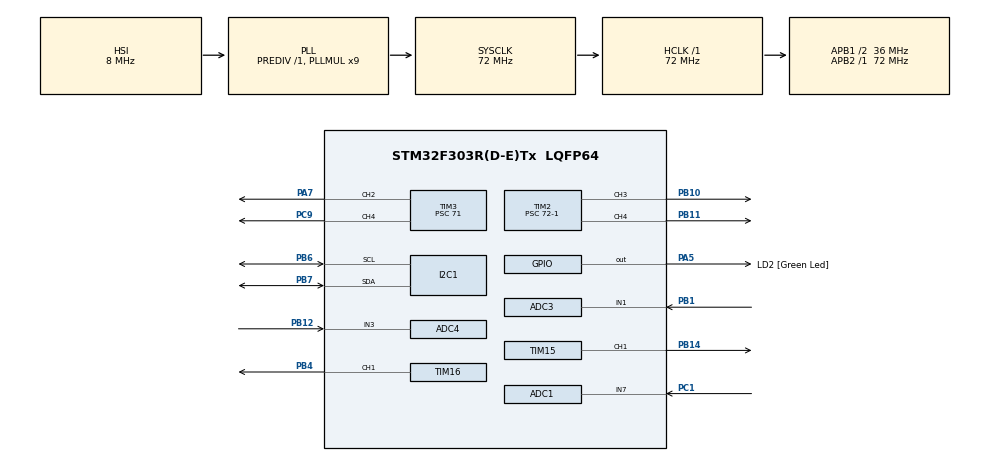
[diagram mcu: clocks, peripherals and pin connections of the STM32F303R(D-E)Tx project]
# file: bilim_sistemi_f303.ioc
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ADC1.Channel-0\#ChannelRegularConversion=ADC_CHANNEL_7
ADC1.NbrOfConversionFlag=1
ADC1.Offset-0\#ChannelRegularConversion=0
ADC1.OffsetNumber-0\#ChannelRegularConversion=ADC_OFFSET_NONE
ADC1.Rank-0\#ChannelRegularConversion=1
ADC1.SamplingTime-0\#ChannelRegularConversion=ADC_SAMPLETIME_19CYCLES_5
ADC1.master=1
ADC3.Channel-0\#ChannelRegularConversion=ADC_CHANNEL_1
ADC3.NbrOfConversionFlag=1
ADC3.Offset-0\#ChannelRegularConversion=0
ADC3.OffsetNumber-0\#ChannelRegularConversion=ADC_OFFSET_NONE
ADC3.Rank-0\#ChannelRegularConversion=1
ADC3.SamplingTime-0\#ChannelRegularConversion=ADC_SAMPLETIME_1CYCLE_5
ADC3.SamplingTimeOPAMP-0\#ChannelRegularConversion=ADC_SAMPLETIME_61CYCLES_5
ADC3.master=1
ADC4.Channel-0\#ChannelRegularConversion=ADC_CHANNEL_3
ADC4.NbrOfConversionFlag=1
ADC4.Offset-0\#ChannelRegularConversion=0
ADC4.OffsetNumber-0\#ChannelRegularConversion=ADC_OFFSET_NONE
ADC4.Rank-0\#ChannelRegularConversion=1
ADC4.SamplingTime-0\#ChannelRegularConversion=ADC_SAMPLETIME_1CYCLE_5
ADC4.SamplingTimeOPAMP-0\#ChannelRegularConversion=ADC_SAMPLETIME_61CYCLES_5
Mcu.Family=STM32F3
Mcu.Name=STM32F303R(D-E)Tx
Mcu.Package=LQFP64
NVIC.PriorityGroup=NVIC_PRIORITYGROUP_0
PA12.Signal=S_TIM4_CH2
PA13.GPIO_Label=TMS
PA13.Mode=Serial_Wire
PA13.Signal=SYS_JTMS-SWDIO
PA14.GPIO_Label=TCK
PA14.Mode=Serial_Wire
PA14.Signal=SYS_JTCK-SWCLK
PA5.GPIO_Label=LD2 [Green Led]
PA5.GPIO_Mode=GPIO_MODE_OUTPUT_PP
PA5.GPIO_PuPd=GPIO_NOPULL
PA5.GPIO_Speed=GPIO_SPEED_FREQ_LOW
PA5.Signal=GPIO_Output
PA7.Signal=S_TIM3_CH2
PB1.Mode=IN1-Single-Ended
PB1.Signal=ADC3_IN1
PB10.Signal=S_TIM2_CH3
PB11.Signal=S_TIM2_CH4
PB12.Mode=IN3-Single-Ended
PB12.Signal=ADC4_IN3
PB14.Signal=S_TIM15_CH1
PB3.GPIO_Label=SWO
PB3.Signal=SYS_JTDO-TRACESWO
PB4.Signal=S_TIM16_CH1
PB6.Mode=I2C
PB6.Signal=I2C1_SCL
PB7.Mode=I2C
PB7.Signal=I2C1_SDA
PC1.Signal=ADCx_IN7
PC9.Signal=S_TIM3_CH4
PF0-OSC_IN.Mode=HSE-External-Clock-Source
PF0-OSC_IN.Signal=RCC_OSC_IN
ProjectManager.HeapSize=0x200
ProjectManager.StackSize=0x400
ProjectManager.TargetToolchain=STM32CubeIDE
RCC.AHBFreq_Value=72000000
RCC.APB1CLKDivider=RCC_HCLK_DIV2
RCC.APB1Freq_Value=36000000
RCC.APB1TimFreq_Value=72000000
RCC.APB2Freq_Value=72000000
RCC.APB2TimFreq_Value=72000000
RCC.CortexFreq_Value=72000000
RCC.HCLKFreq_Value=72000000
RCC.HSE_VALUE=8000000
RCC.HSI_VALUE=8000000
RCC.LSE_VALUE=32768
RCC.PLLM=8
RCC.PLLMUL=RCC_PLL_MUL9
RCC.PLLN=336
RCC.PLLP=RCC_PLLP_DIV4
RCC.PLLQ=7
RCC.PRESCALERUSB=RCC_USBCLKSOURCE_PLL_DIV1_5
RCC.RCC_PLLsource_Clock_Source_FROM_HSE=RCC_HSE_PREDIV_DIV2
RCC.SYSCLKFreq_VALUE=72000000
RCC.SYSCLKSourceVirtual=RCC_SYSCLKSOURCE_PLLCLK
RCC.USBFreq_Value=48000000
SH.ADCx_IN7.0=ADC1_IN7,IN7-Single-Ended
SH.S_TIM15_CH1.0=TIM15_CH1,PWM Generation1 CH1
SH.S_TIM16_CH1.0=TIM16_CH1,PWM Generation1 CH1
SH.S_TIM2_CH3.0=TIM2_CH3,PWM Generation3 CH3
SH.S_TIM2_CH4.0=TIM2_CH4,PWM Generation4 CH4
SH.S_TIM3_CH2.0=TIM3_CH2,PWM Generation2 CH2
SH.S_TIM3_CH4.0=TIM3_CH4,PWM Generation4 CH4
SH.S_TIM4_CH2.0=TIM4_CH2
TIM15.Channel-PWM\ Generation1\ CH1=TIM_CHANNEL_1
TIM15.Period=100
TIM15.Prescaler=71
TIM16.Channel=TIM_CHANNEL_1
TIM16.Period=100-1
TIM16.Prescaler=72-1
TIM16.Pulse=0
TIM2.Channel-PWM\ Generation3\ CH3=TIM_CHANNEL_3
TIM2.Channel-PWM\ Generation4\ CH4=TIM_CHANNEL_4
TIM2.Period=100-1
TIM2.Prescaler=72-1
TIM3.Channel-PWM\ Generation2\ CH2=TIM_CHANNEL_2
TIM3.Channel-PWM\ Generation4\ CH4=TIM_CHANNEL_4
TIM3.Period=99
TIM3.Prescaler=71
TIM8.Prescaler=71
VP_TIM16_VS_ClockSourceINT.Mode=Enable_Timer
VP_TIM1_VS_ClockSourceINT.Mode=Internal
VP_TIM2_VS_ClockSourceINT.Mode=Internal
VP_TIM8_VS_ClockSourceINT.Mode=Internal
board=NUCLEO-F303RE

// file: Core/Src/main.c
/* USER CODE BEGIN Header */
/**
  ******************************************************************************
  * @file           : main.c
  * @brief          : Main program body
  ******************************************************************************
  * @attention
  *
  * Copyright (c) 2024 STMicroelectronics.
  * All rights reserved.
  *
  * This software is licensed under terms that can be found in the LICENSE file
  * in the root directory of this software component.
  * If no LICENSE file comes with this software, it is provided AS-IS.
  *
  ******************************************************************************
  */
/* USER CODE END Header */
#include "main.h"

/* USER CODE BEGIN Includes */
#include "BMP180.h"
#include "MQ.h"
#include "mk_dht11.h"

/* USER CODE END Includes */

/* USER CODE BEGIN PD */
MQ mq137;
MQ mq4;
MQ mq135;
dht11_t DHT11;

/* USER CODE END PD */

ADC_HandleTypeDef hadc1;
ADC_HandleTypeDef hadc3;
ADC_HandleTypeDef hadc4;

I2C_HandleTypeDef hi2c1;

TIM_HandleTypeDef htim1;
TIM_HandleTypeDef htim2;
TIM_HandleTypeDef htim3;
TIM_HandleTypeDef htim8;
TIM_HandleTypeDef htim15;
TIM_HandleTypeDef htim16;

/* USER CODE BEGIN PV */
float TEMP;
float PRESS;
float temp = 0;
float hum = 0;
float nh3_ppm = 0;
float ch4_ppm = 0;
float co2_ppm = 0;
uint8_t dht_temp = 0;
uint8_t dht_hum = 0;
uint8_t Lim_s1=0;
uint8_t Lim_s2=0;

/* USER CODE END PV */

void SystemClock_Config(void);
static void MX_GPIO_Init(void);
static void MX_I2C1_Init(void);
static void MX_ADC1_Init(void);
static void MX_TIM1_Init(void);
static void MX_TIM8_Init(void);
static void MX_ADC3_Init(void);
static void MX_ADC4_Init(void);
static void MX_TIM16_Init(void);
static void MX_TIM2_Init(void);
static void MX_TIM3_Init(void);
static void MX_TIM15_Init(void);
/* USER CODE BEGIN PFP */

void EXTI10_15_IRQHandler(void)   // <----- The ISR Function We're Looking For!
{
	if(HAL_GPIO_ReadPin(GPIOC, GPIO_PIN_10)==1){
		HAL_GPIO_EXTI_IRQHandler(GPIO_PIN_10);
	}
	if(HAL_GPIO_ReadPin(GPIOC, GPIO_PIN_11)==1){
			HAL_GPIO_EXTI_IRQHandler(GPIO_PIN_11);
		}
}
void HAL_GPIO_EXTI_Callback(uint16_t GPIO_Pin)
{
    if(GPIO_Pin == GPIO_PIN_10) // If The INT Source Is EXTI Line9 (A9 Pin)
    {
    Lim_s1 = 1; // Toggle The Output (LED) Pin
    }
    if(GPIO_Pin == GPIO_PIN_11) // If The INT Source Is EXTI Line9 (A9 Pin)
    {
    Lim_s2 = 1; // Toggle The Output (LED) Pin
    }
}

/* USER CODE END PFP */

int main(void)
{

  /* MCU Configuration--------------------------------------------------------*/

  /* Reset of all peripherals, Initializes the Flash interface and the Systick. */
																																																																													HAL_Init();

  /* Configure the system clock */
  SystemClock_Config();

  /* Initialize all configured peripherals */
  MX_GPIO_Init();
  MX_I2C1_Init();
  MX_ADC1_Init();
  MX_TIM1_Init();
  MX_TIM8_Init();
  MX_ADC3_Init();
  MX_ADC4_Init();
  MX_TIM16_Init();
  MX_TIM2_Init();
  MX_TIM3_Init();
  MX_TIM15_Init();
  /* USER CODE BEGIN 2 */

  //SENSOR INITS
  init_dht11(&DHT11,&htim8,GPIOC,GPIO_PIN_8);
  BMP180_Init(&hi2c1);
  MQ_Init(&mq137,&hadc1,temp,hum);
  MQ_Init(&mq4,&hadc4,temp,hum);
  MQ_Init(&mq135,&hadc3,temp,hum);

  //PWM INITS
  //CCR Registerine verilen değerler duty cycle yüzdesini ifade eder.
  //SAĞDAN 1. VICTOR
  HAL_TIM_PWM_Init(&htim2);
  HAL_TIM_PWM_Start(&htim2, TIM_CHANNEL_3);
  TIM2->CCR3 = 0;
  //SAĞDAN 2.VICTOR
  HAL_TIM_PWM_Init(&htim16);
  HAL_TIM_PWM_Start(&htim16, TIM_CHANNEL_1);
  TIM16->CCR1 = 0;
  //SAĞDAN 3.VICTOR(YEDEK VICTOR)
  HAL_TIM_PWM_Init(&htim3);
  HAL_TIM_PWM_Start(&htim3, TIM_CHANNEL_4);
  TIM3->CCR4 = 0;

  //SAĞDAN 1.POMPA
  HAL_TIM_PWM_Start(&htim2, TIM_CHANNEL_4);
  TIM2->CCR4 = 0;
  //SAĞDAN 3.POMPA
  HAL_TIM_PWM_Start(&htim3, TIM_CHANNEL_2);
  TIM3->CCR2 = 0;
  //SAĞDAN 2.POMPA(YEDEK POMPA)
  HAL_TIM_PWM_Init(&htim15);
  HAL_TIM_PWM_Start(&htim15, TIM_CHANNEL_1);
  TIM15->CCR1 = 0;
  /* USER CODE END 2 */

  /* Infinite loop */
  while (1)
  {

    /* USER CODE BEGIN 3 */
	  if (readDHT11(&DHT11)){

	  dht_temp=DHT11.temperature_I;
	  dht_hum=DHT11.humidty_I;
	  update_tempHum(&mq135, dht_temp, dht_hum);
	  update_tempHum(&mq137, dht_temp, dht_hum);
	  update_tempHum(&mq4, dht_temp, dht_hum);
	  }
	  //corrected : dht11 den gelen sıcaklık ve nem verilerine göre düzeltilmiş youğunluk.
	  //dht11 mevcut değilse gerekli sıcaklık ve nem değerleri elle atanmalı ve sabit kalmalı
	  //sıcaklık ve nem değerleri olmaksızın hesap yapılmak isteniyorsa getcorrected..()  yeribe get..() fonksiyonları kullanılmalı
	  nh3_ppm = getCorrectedNH3(&mq137);
	  co2_ppm = getCorrectedCO2(&mq135);
	  ch4_ppm = getCorrectedCH4(&mq4);
	  TEMP =  BMP180_GetTemp();
	  PRESS = BMP180_GetPress();
	  HAL_Delay(100);
  }
  /* USER CODE END 3 */
}

void SystemClock_Config(void)
{
  RCC_OscInitTypeDef RCC_OscInitStruct = {0};
  RCC_ClkInitTypeDef RCC_ClkInitStruct = {0};
  RCC_PeriphCLKInitTypeDef PeriphClkInit = {0};

  /** Initializes the RCC Oscillators according to the specified parameters
  * in the RCC_OscInitTypeDef structure.
  */
  RCC_OscInitStruct.OscillatorType = RCC_OSCILLATORTYPE_HSI;
  RCC_OscInitStruct.HSIState = RCC_HSI_ON;
  RCC_OscInitStruct.HSICalibrationValue = RCC_HSICALIBRATION_DEFAULT;
  RCC_OscInitStruct.PLL.PLLState = RCC_PLL_ON;
  RCC_OscInitStruct.PLL.PLLSource = RCC_PLLSOURCE_HSI;
  RCC_OscInitStruct.PLL.PLLMUL = RCC_PLL_MUL9;
  RCC_OscInitStruct.PLL.PREDIV = RCC_PREDIV_DIV1;
  if (HAL_RCC_OscConfig(&RCC_OscInitStruct) != HAL_OK)
  {
    Error_Handler();
  }

  /** Initializes the CPU, AHB and APB buses clocks
  */
  RCC_ClkInitStruct.ClockType = RCC_CLOCKTYPE_HCLK|RCC_CLOCKTYPE_SYSCLK
                              |RCC_CLOCKTYPE_PCLK1|RCC_CLOCKTYPE_PCLK2;
  RCC_ClkInitStruct.SYSCLKSource = RCC_SYSCLKSOURCE_PLLCLK;
  RCC_ClkInitStruct.AHBCLKDivider = RCC_SYSCLK_DIV1;
  RCC_ClkInitStruct.APB1CLKDivider = RCC_HCLK_DIV2;
  RCC_ClkInitStruct.APB2CLKDivider = RCC_HCLK_DIV1;

  if (HAL_RCC_ClockConfig(&RCC_ClkInitStruct, FLASH_LATENCY_2) != HAL_OK)
  {
    Error_Handler();
  }
  PeriphClkInit.PeriphClockSelection = RCC_PERIPHCLK_I2C1|RCC_PERIPHCLK_TIM1
                              |RCC_PERIPHCLK_TIM15|RCC_PERIPHCLK_TIM16
                              |RCC_PERIPHCLK_TIM8|RCC_PERIPHCLK_ADC12
                              |RCC_PERIPHCLK_ADC34|RCC_PERIPHCLK_TIM2
                              |RCC_PERIPHCLK_TIM34;
  PeriphClkInit.Adc12ClockSelection = RCC_ADC12PLLCLK_DIV1;
  PeriphClkInit.Adc34ClockSelection = RCC_ADC34PLLCLK_DIV1;
  PeriphClkInit.I2c1ClockSelection = RCC_I2C1CLKSOURCE_HSI;
  PeriphClkInit.Tim1ClockSelection = RCC_TIM1CLK_HCLK;
  PeriphClkInit.Tim15ClockSelection = RCC_TIM15CLK_HCLK;
  PeriphClkInit.Tim16ClockSelection = RCC_TIM16CLK_HCLK;
  PeriphClkInit.Tim8ClockSelection = RCC_TIM8CLK_HCLK;
  PeriphClkInit.Tim2ClockSelection = RCC_TIM2CLK_HCLK;
  PeriphClkInit.Tim34ClockSelection = RCC_TIM34CLK_HCLK;
  if (HAL_RCCEx_PeriphCLKConfig(&PeriphClkInit) != HAL_OK)
  {
    Error_Handler();
  }
}

static void MX_ADC1_Init(void)
{

  ADC_MultiModeTypeDef multimode = {0};
  ADC_ChannelConfTypeDef sConfig = {0};

  /** Common config
  */
  hadc1.Instance = ADC1;
  hadc1.Init.ClockPrescaler = ADC_CLOCK_ASYNC_DIV1;
  hadc1.Init.Resolution = ADC_RESOLUTION_12B;
  hadc1.Init.ScanConvMode = ADC_SCAN_DISABLE;
  hadc1.Init.ContinuousConvMode = DISABLE;
  hadc1.Init.DiscontinuousConvMode = DISABLE;
  hadc1.Init.ExternalTrigConvEdge = ADC_EXTERNALTRIGCONVEDGE_NONE;
  hadc1.Init.ExternalTrigConv = ADC_SOFTWARE_START;
  hadc1.Init.DataAlign = ADC_DATAALIGN_RIGHT;
  hadc1.Init.NbrOfConversion = 1;
  hadc1.Init.DMAContinuousRequests = DISABLE;
  hadc1.Init.EOCSelection = ADC_EOC_SINGLE_CONV;
  hadc1.Init.LowPowerAutoWait = DISABLE;
  hadc1.Init.Overrun = ADC_OVR_DATA_OVERWRITTEN;
  if (HAL_ADC_Init(&hadc1) != HAL_OK)
  {
    Error_Handler();
  }

  /** Configure the ADC multi-mode
  */
  multimode.Mode = ADC_MODE_INDEPENDENT;
  if (HAL_ADCEx_MultiModeConfigChannel(&hadc1, &multimode) != HAL_OK)
  {
    Error_Handler();
  }

  /** Configure Regular Channel
  */
  sConfig.Channel = ADC_CHANNEL_7;
  sConfig.Rank = ADC_REGULAR_RANK_1;
  sConfig.SingleDiff = ADC_SINGLE_ENDED;
  sConfig.SamplingTime = ADC_SAMPLETIME_19CYCLES_5;
  sConfig.OffsetNumber = ADC_OFFSET_NONE;
  sConfig.Offset = 0;
  if (HAL_ADC_ConfigChannel(&hadc1, &sConfig) != HAL_OK)
  {
    Error_Handler();
  }

}

static void MX_ADC3_Init(void)
{

  ADC_MultiModeTypeDef multimode = {0};
  ADC_ChannelConfTypeDef sConfig = {0};

  /** Common config
  */
  hadc3.Instance = ADC3;
  hadc3.Init.ClockPrescaler = ADC_CLOCK_ASYNC_DIV1;
  hadc3.Init.Resolution = ADC_RESOLUTION_12B;
  hadc3.Init.ScanConvMode = ADC_SCAN_DISABLE;
  hadc3.Init.ContinuousConvMode = DISABLE;
  hadc3.Init.DiscontinuousConvMode = DISABLE;
  hadc3.Init.ExternalTrigConvEdge = ADC_EXTERNALTRIGCONVEDGE_NONE;
  hadc3.Init.ExternalTrigConv = ADC_SOFTWARE_START;
  hadc3.Init.DataAlign = ADC_DATAALIGN_RIGHT;
  hadc3.Init.NbrOfConversion = 1;
  hadc3.Init.DMAContinuousRequests = DISABLE;
  hadc3.Init.EOCSelection = ADC_EOC_SINGLE_CONV;
  hadc3.Init.LowPowerAutoWait = DISABLE;
  hadc3.Init.Overrun = ADC_OVR_DATA_OVERWRITTEN;
  if (HAL_ADC_Init(&hadc3) != HAL_OK)
  {
    Error_Handler();
  }

  /** Configure the ADC multi-mode
  */
  multimode.Mode = ADC_MODE_INDEPENDENT;
  if (HAL_ADCEx_MultiModeConfigChannel(&hadc3, &multimode) != HAL_OK)
  {
    Error_Handler();
  }

  /** Configure Regular Channel
  */
  sConfig.Channel = ADC_CHANNEL_1;
  sConfig.Rank = ADC_REGULAR_RANK_1;
  sConfig.SingleDiff = ADC_SINGLE_ENDED;
  sConfig.SamplingTime = ADC_SAMPLETIME_1CYCLE_5;
  sConfig.OffsetNumber = ADC_OFFSET_NONE;
  sConfig.Offset = 0;
  if (HAL_ADC_ConfigChannel(&hadc3, &sConfig) != HAL_OK)
  {
    Error_Handler();
  }

}

static void MX_ADC4_Init(void)
{

  ADC_ChannelConfTypeDef sConfig = {0};

  /** Common config
  */
  hadc4.Instance = ADC4;
  hadc4.Init.ClockPrescaler = ADC_CLOCK_ASYNC_DIV1;
  hadc4.Init.Resolution = ADC_RESOLUTION_12B;
  hadc4.Init.ScanConvMode = ADC_SCAN_DISABLE;
  hadc4.Init.ContinuousConvMode = DISABLE;
  hadc4.Init.DiscontinuousConvMode = DISABLE;
  hadc4.Init.ExternalTrigConvEdge = ADC_EXTERNALTRIGCONVEDGE_NONE;
  hadc4.Init.ExternalTrigConv = ADC_SOFTWARE_START;
  hadc4.Init.DataAlign = ADC_DATAALIGN_RIGHT;
  hadc4.Init.NbrOfConversion = 1;
  hadc4.Init.DMAContinuousRequests = DISABLE;
  hadc4.Init.EOCSelection = ADC_EOC_SINGLE_CONV;
  hadc4.Init.LowPowerAutoWait = DISABLE;
  hadc4.Init.Overrun = ADC_OVR_DATA_OVERWRITTEN;
  if (HAL_ADC_Init(&hadc4) != HAL_OK)
  {
    Error_Handler();
  }

  /** Configure Regular Channel
  */
  sConfig.Channel = ADC_CHANNEL_3;
  sConfig.Rank = ADC_REGULAR_RANK_1;
  sConfig.SingleDiff = ADC_SINGLE_ENDED;
  sConfig.SamplingTime = ADC_SAMPLETIME_1CYCLE_5;
  sConfig.OffsetNumber = ADC_OFFSET_NONE;
  sConfig.Offset = 0;
  if (HAL_ADC_ConfigChannel(&hadc4, &sConfig) != HAL_OK)
  {
    Error_Handler();
  }

}

static void MX_I2C1_Init(void)
{

  hi2c1.Instance = I2C1;
  hi2c1.Init.Timing = 0x2000090E;
  hi2c1.Init.OwnAddress1 = 0;
  hi2c1.Init.AddressingMode = I2C_ADDRESSINGMODE_7BIT;
  hi2c1.Init.DualAddressMode = I2C_DUALADDRESS_DISABLE;
  hi2c1.Init.OwnAddress2 = 0;
  hi2c1.Init.OwnAddress2Masks = I2C_OA2_NOMASK;
  hi2c1.Init.GeneralCallMode = I2C_GENERALCALL_DISABLE;
  hi2c1.Init.NoStretchMode = I2C_NOSTRETCH_DISABLE;
  if (HAL_I2C_Init(&hi2c1) != HAL_OK)
  {
    Error_Handler();
  }

  /** Configure Analogue filter
  */
  if (HAL_I2CEx_ConfigAnalogFilter(&hi2c1, I2C_ANALOGFILTER_ENABLE) != HAL_OK)
  {
    Error_Handler();
  }

  /** Configure Digital filter
  */
  if (HAL_I2CEx_ConfigDigitalFilter(&hi2c1, 0) != HAL_OK)
  {
    Error_Handler();
  }

}

static void MX_TIM1_Init(void)
{

  TIM_ClockConfigTypeDef sClockSourceConfig = {0};
  TIM_MasterConfigTypeDef sMasterConfig = {0};

  htim1.Instance = TIM1;
  htim1.Init.Prescaler = 0;
  htim1.Init.CounterMode = TIM_COUNTERMODE_UP;
  htim1.Init.Period = 65535;
  htim1.Init.ClockDivision = TIM_CLOCKDIVISION_DIV1;
  htim1.Init.RepetitionCounter = 0;
  htim1.Init.AutoReloadPreload = TIM_AUTORELOAD_PRELOAD_DISABLE;
  if (HAL_TIM_Base_Init(&htim1) != HAL_OK)
  {
    Error_Handler();
  }
  sClockSourceConfig.ClockSource = TIM_CLOCKSOURCE_INTERNAL;
  if (HAL_TIM_ConfigClockSource(&htim1, &sClockSourceConfig) != HAL_OK)
  {
    Error_Handler();
  }
  sMasterConfig.MasterOutputTrigger = TIM_TRGO_RESET;
  sMasterConfig.MasterOutputTrigger2 = TIM_TRGO2_RESET;
  sMasterConfig.MasterSlaveMode = TIM_MASTERSLAVEMODE_DISABLE;
  if (HAL_TIMEx_MasterConfigSynchronization(&htim1, &sMasterConfig) != HAL_OK)
  {
    Error_Handler();
  }

}

static void MX_TIM2_Init(void)
{

  TIM_ClockConfigTypeDef sClockSourceConfig = {0};
  TIM_MasterConfigTypeDef sMasterConfig = {0};
  TIM_OC_InitTypeDef sConfigOC = {0};

  htim2.Instance = TIM2;
  htim2.Init.Prescaler = 72-1;
  htim2.Init.CounterMode = TIM_COUNTERMODE_UP;
  htim2.Init.Period = 100-1;
  htim2.Init.ClockDivision = TIM_CLOCKDIVISION_DIV1;
  htim2.Init.AutoReloadPreload = TIM_AUTORELOAD_PRELOAD_DISABLE;
  if (HAL_TIM_Base_Init(&htim2) != HAL_OK)
  {
    Error_Handler();
  }
  sClockSourceConfig.ClockSource = TIM_CLOCKSOURCE_INTERNAL;
  if (HAL_TIM_ConfigClockSource(&htim2, &sClockSourceConfig) != HAL_OK)
  {
    Error_Handler();
  }
  if (HAL_TIM_PWM_Init(&htim2) != HAL_OK)
  {
    Error_Handler();
  }
  sMasterConfig.MasterOutputTrigger = TIM_TRGO_RESET;
  sMasterConfig.MasterSlaveMode = TIM_MASTERSLAVEMODE_DISABLE;
  if (HAL_TIMEx_MasterConfigSynchronization(&htim2, &sMasterConfig) != HAL_OK)
  {
    Error_Handler();
  }
  sConfigOC.OCMode = TIM_OCMODE_PWM1;
  sConfigOC.Pulse = 0;
  sConfigOC.OCPolarity = TIM_OCPOLARITY_HIGH;
  sConfigOC.OCFastMode = TIM_OCFAST_DISABLE;
  if (HAL_TIM_PWM_ConfigChannel(&htim2, &sConfigOC, TIM_CHANNEL_3) != HAL_OK)
  {
    Error_Handler();
  }
  if (HAL_TIM_PWM_ConfigChannel(&htim2, &sConfigOC, TIM_CHANNEL_4) != HAL_OK)
  {
    Error_Handler();
  }
  HAL_TIM_MspPostInit(&htim2);

}

static void MX_TIM3_Init(void)
{

  TIM_MasterConfigTypeDef sMasterConfig = {0};
  TIM_OC_InitTypeDef sConfigOC = {0};

  htim3.Instance = TIM3;
  htim3.Init.Prescaler = 71;
  htim3.Init.CounterMode = TIM_COUNTERMODE_UP;
  htim3.Init.Period = 99;
  htim3.Init.ClockDivision = TIM_CLOCKDIVISION_DIV1;
  htim3.Init.AutoReloadPreload = TIM_AUTORELOAD_PRELOAD_DISABLE;
  if (HAL_TIM_PWM_Init(&htim3) != HAL_OK)
  {
    Error_Handler();
  }
  sMasterConfig.MasterOutputTrigger = TIM_TRGO_RESET;
  sMasterConfig.MasterSlaveMode = TIM_MASTERSLAVEMODE_DISABLE;
  if (HAL_TIMEx_MasterConfigSynchronization(&htim3, &sMasterConfig) != HAL_OK)
  {
    Error_Handler();
  }
  sConfigOC.OCMode = TIM_OCMODE_PWM1;
  sConfigOC.Pulse = 0;
  sConfigOC.OCPolarity = TIM_OCPOLARITY_HIGH;
  sConfigOC.OCFastMode = TIM_OCFAST_DISABLE;
  if (HAL_TIM_PWM_ConfigChannel(&htim3, &sConfigOC, TIM_CHANNEL_2) != HAL_OK)
  {
    Error_Handler();
  }
  if (HAL_TIM_PWM_ConfigChannel(&htim3, &sConfigOC, TIM_CHANNEL_4) != HAL_OK)
  {
    Error_Handler();
  }
  HAL_TIM_MspPostInit(&htim3);

}

static void MX_TIM8_Init(void)
{

  TIM_ClockConfigTypeDef sClockSourceConfig = {0};
  TIM_MasterConfigTypeDef sMasterConfig = {0};

  htim8.Instance = TIM8;
  htim8.Init.Prescaler = 71;
  htim8.Init.CounterMode = TIM_COUNTERMODE_UP;
  htim8.Init.Period = 65535;
  htim8.Init.ClockDivision = TIM_CLOCKDIVISION_DIV1;
  htim8.Init.RepetitionCounter = 0;
  htim8.Init.AutoReloadPreload = TIM_AUTORELOAD_PRELOAD_DISABLE;
  if (HAL_TIM_Base_Init(&htim8) != HAL_OK)
  {
    Error_Handler();
  }
  sClockSourceConfig.ClockSource = TIM_CLOCKSOURCE_INTERNAL;
  if (HAL_TIM_ConfigClockSource(&htim8, &sClockSourceConfig) != HAL_OK)
  {
    Error_Handler();
  }
  sMasterConfig.MasterOutputTrigger = TIM_TRGO_RESET;
  sMasterConfig.MasterOutputTrigger2 = TIM_TRGO2_RESET;
  sMasterConfig.MasterSlaveMode = TIM_MASTERSLAVEMODE_DISABLE;
  if (HAL_TIMEx_MasterConfigSynchronization(&htim8, &sMasterConfig) != HAL_OK)
  {
    Error_Handler();
  }

}

static void MX_TIM15_Init(void)
{

  TIM_MasterConfigTypeDef sMasterConfig = {0};
  TIM_OC_InitTypeDef sConfigOC = {0};
  TIM_BreakDeadTimeConfigTypeDef sBreakDeadTimeConfig = {0};

  htim15.Instance = TIM15;
  htim15.Init.Prescaler = 71;
  htim15.Init.CounterMode = TIM_COUNTERMODE_UP;
  htim15.Init.Period = 100;
  htim15.Init.ClockDivision = TIM_CLOCKDIVISION_DIV1;
  htim15.Init.RepetitionCounter = 0;
  htim15.Init.AutoReloadPreload = TIM_AUTORELOAD_PRELOAD_DISABLE;
  if (HAL_TIM_PWM_Init(&htim15) != HAL_OK)
  {
    Error_Handler();
  }
  sMasterConfig.MasterOutputTrigger = TIM_TRGO_RESET;
  sMasterConfig.MasterSlaveMode = TIM_MASTERSLAVEMODE_DISABLE;
  if (HAL_TIMEx_MasterConfigSynchronization(&htim15, &sMasterConfig) != HAL_OK)
  {
    Error_Handler();
  }
  sConfigOC.OCMode = TIM_OCMODE_PWM1;
  sConfigOC.Pulse = 0;
  sConfigOC.OCPolarity = TIM_OCPOLARITY_HIGH;
  sConfigOC.OCNPolarity = TIM_OCNPOLARITY_HIGH;
  sConfigOC.OCFastMode = TIM_OCFAST_DISABLE;
  sConfigOC.OCIdleState = TIM_OCIDLESTATE_RESET;
  sConfigOC.OCNIdleState = TIM_OCNIDLESTATE_RESET;
  if (HAL_TIM_PWM_ConfigChannel(&htim15, &sConfigOC, TIM_CHANNEL_1) != HAL_OK)
  {
    Error_Handler();
  }
  sBreakDeadTimeConfig.OffStateRunMode = TIM_OSSR_DISABLE;
  sBreakDeadTimeConfig.OffStateIDLEMode = TIM_OSSI_DISABLE;
  sBreakDeadTimeConfig.LockLevel = TIM_LOCKLEVEL_OFF;
  sBreakDeadTimeConfig.DeadTime = 0;
  sBreakDeadTimeConfig.BreakState = TIM_BREAK_DISABLE;
  sBreakDeadTimeConfig.BreakPolarity = TIM_BREAKPOLARITY_HIGH;
  sBreakDeadTimeConfig.BreakFilter = 0;
  sBreakDeadTimeConfig.AutomaticOutput = TIM_AUTOMATICOUTPUT_DISABLE;
  if (HAL_TIMEx_ConfigBreakDeadTime(&htim15, &sBreakDeadTimeConfig) != HAL_OK)
  {
    Error_Handler();
  }
  HAL_TIM_MspPostInit(&htim15);

}

static void MX_TIM16_Init(void)
{

  TIM_OC_InitTypeDef sConfigOC = {0};
  TIM_BreakDeadTimeConfigTypeDef sBreakDeadTimeConfig = {0};

  htim16.Instance = TIM16;
  htim16.Init.Prescaler = 72-1;
  htim16.Init.CounterMode = TIM_COUNTERMODE_UP;
  htim16.Init.Period = 100-1;
  htim16.Init.ClockDivision = TIM_CLOCKDIVISION_DIV1;
  htim16.Init.RepetitionCounter = 0;
  htim16.Init.AutoReloadPreload = TIM_AUTORELOAD_PRELOAD_DISABLE;
  if (HAL_TIM_Base_Init(&htim16) != HAL_OK)
  {
    Error_Handler();
  }
  if (HAL_TIM_PWM_Init(&htim16) != HAL_OK)
  {
    Error_Handler();
  }
  sConfigOC.OCMode = TIM_OCMODE_PWM1;
  sConfigOC.Pulse = 0;
  sConfigOC.OCPolarity = TIM_OCPOLARITY_HIGH;
  sConfigOC.OCNPolarity = TIM_OCNPOLARITY_HIGH;
  sConfigOC.OCFastMode = TIM_OCFAST_DISABLE;
  sConfigOC.OCIdleState = TIM_OCIDLESTATE_RESET;
  sConfigOC.OCNIdleState = TIM_OCNIDLESTATE_RESET;
  if (HAL_TIM_PWM_ConfigChannel(&htim16, &sConfigOC, TIM_CHANNEL_1) != HAL_OK)
  {
    Error_Handler();
  }
  sBreakDeadTimeConfig.OffStateRunMode = TIM_OSSR_DISABLE;
  sBreakDeadTimeConfig.OffStateIDLEMode = TIM_OSSI_DISABLE;
  sBreakDeadTimeConfig.LockLevel = TIM_LOCKLEVEL_OFF;
  sBreakDeadTimeConfig.DeadTime = 0;
  sBreakDeadTimeConfig.BreakState = TIM_BREAK_DISABLE;
  sBreakDeadTimeConfig.BreakPolarity = TIM_BREAKPOLARITY_HIGH;
  sBreakDeadTimeConfig.BreakFilter = 0;
  sBreakDeadTimeConfig.AutomaticOutput = TIM_AUTOMATICOUTPUT_DISABLE;
  if (HAL_TIMEx_ConfigBreakDeadTime(&htim16, &sBreakDeadTimeConfig) != HAL_OK)
  {
    Error_Handler();
  }
  HAL_TIM_MspPostInit(&htim16);

}

static void MX_GPIO_Init(void)
{
  GPIO_InitTypeDef GPIO_InitStruct = {0};

  /* GPIO Ports Clock Enable */
  __HAL_RCC_GPIOF_CLK_ENABLE();
  __HAL_RCC_GPIOC_CLK_ENABLE();
  __HAL_RCC_GPIOA_CLK_ENABLE();
  __HAL_RCC_GPIOB_CLK_ENABLE();

  /*Configure GPIO pin Output Level */
  HAL_GPIO_WritePin(LD2_GPIO_Port, LD2_Pin, GPIO_PIN_RESET);

  /*Configure GPIO pin : LD2_Pin */
  GPIO_InitStruct.Pin = LD2_Pin;
  GPIO_InitStruct.Mode = GPIO_MODE_OUTPUT_PP;
  GPIO_InitStruct.Pull = GPIO_NOPULL;
  GPIO_InitStruct.Speed = GPIO_SPEED_FREQ_LOW;
  HAL_GPIO_Init(LD2_GPIO_Port, &GPIO_InitStruct);

  /*Configure GPIO pin : PA12 */
  GPIO_InitStruct.Pin = GPIO_PIN_12;
  GPIO_InitStruct.Mode = GPIO_MODE_AF_PP;
  GPIO_InitStruct.Pull = GPIO_NOPULL;
  GPIO_InitStruct.Speed = GPIO_SPEED_FREQ_LOW;
  GPIO_InitStruct.Alternate = GPIO_AF10_TIM4;
  HAL_GPIO_Init(GPIOA, &GPIO_InitStruct);

  /*Configure GPIO pins : PC10 PC11 */
  GPIO_InitStruct.Pin = GPIO_PIN_10|GPIO_PIN_11;
  GPIO_InitStruct.Mode = GPIO_MODE_IT_RISING;
  GPIO_InitStruct.Pull = GPIO_NOPULL;
  HAL_GPIO_Init(GPIOC, &GPIO_InitStruct);

  /* EXTI interrupt init*/
  HAL_NVIC_SetPriority(EXTI15_10_IRQn, 0, 0);
  HAL_NVIC_EnableIRQ(EXTI15_10_IRQn);

}

void Error_Handler(void)
{
  __disable_irq();
  while (1)
  {
  }
}
